VERSION 5.7 ;
  NOWIREEXTENSIONATPIN ON ;
  DIVIDERCHAR "/" ;
  BUSBITCHARS "[]" ;
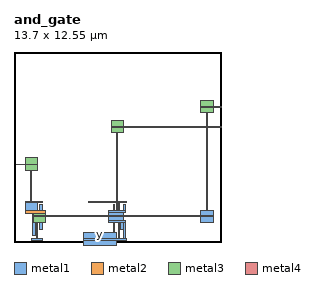
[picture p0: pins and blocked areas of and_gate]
MACRO and_gate
  CLASS BLOCK ;
  FOREIGN and_gate ;
  ORIGIN 1.150 0.200 ;
  SIZE 13.700 BY 12.550 ;
  PIN y
    PORT
      LAYER metal1 ;
        RECT -0.400 2.400 0.750 2.500 ;
        RECT 3.800 2.400 6.250 2.500 ;
        RECT -0.400 1.900 0.400 2.400 ;
        RECT 0.550 1.900 0.700 2.300 ;
        RECT 5.450 1.900 5.500 2.300 ;
        RECT 5.750 1.900 5.800 2.400 ;
        RECT 6.100 1.900 6.200 2.250 ;
        RECT -0.400 1.700 0.950 1.900 ;
        RECT 0.050 1.100 0.950 1.700 ;
        RECT 5.100 1.750 6.200 1.900 ;
        RECT 5.100 1.550 6.100 1.750 ;
        RECT 11.200 1.550 12.000 1.900 ;
        RECT 5.100 1.500 12.000 1.550 ;
        RECT 5.100 1.200 6.100 1.500 ;
        RECT 5.100 1.100 6.200 1.200 ;
        RECT 11.200 1.100 12.000 1.500 ;
        RECT 0.050 0.200 0.250 1.100 ;
        RECT 0.350 0.050 0.400 1.100 ;
        RECT 0.550 0.650 0.700 1.100 ;
        RECT 5.450 0.400 5.500 1.100 ;
        RECT 3.450 0.050 5.650 0.400 ;
        RECT 5.750 0.050 5.800 1.100 ;
        RECT 5.900 0.650 6.050 1.100 ;
        RECT 6.100 0.050 6.200 1.100 ;
        RECT 0.000 -0.100 0.750 0.050 ;
        RECT 3.450 -0.100 6.250 0.050 ;
        RECT 3.450 -0.400 5.650 -0.100 ;
      LAYER metal2 ;
        RECT 11.200 8.350 12.000 9.150 ;
        RECT 5.300 7.000 6.100 7.800 ;
        RECT -0.400 4.550 0.400 5.350 ;
        RECT -0.050 2.500 0.000 4.550 ;
        RECT -0.400 1.900 0.400 2.500 ;
        RECT 5.650 1.900 5.700 7.000 ;
        RECT 11.550 1.900 11.600 8.350 ;
        RECT -0.400 1.700 0.950 1.900 ;
        RECT 0.150 1.100 0.950 1.700 ;
        RECT 5.100 1.100 6.100 1.900 ;
        RECT 11.200 1.100 12.000 1.900 ;
        RECT 3.450 -0.400 5.650 0.400 ;
      LAYER metal3 ;
        RECT 11.200 8.750 12.000 9.150 ;
        RECT 11.200 8.700 12.550 8.750 ;
        RECT 11.200 8.350 12.000 8.700 ;
        RECT 5.300 7.400 6.100 7.800 ;
        RECT 5.300 7.350 12.550 7.400 ;
        RECT 5.300 7.000 6.100 7.350 ;
        RECT -0.400 4.950 0.400 5.350 ;
        RECT -1.000 4.900 0.400 4.950 ;
        RECT -0.400 4.550 0.400 4.900 ;
        RECT 0.150 1.550 0.950 1.900 ;
        RECT 5.100 1.550 5.900 1.900 ;
        RECT 0.150 1.500 5.900 1.550 ;
        RECT 0.150 1.100 0.950 1.500 ;
        RECT 5.100 1.100 5.900 1.500 ;
        RECT 3.450 -0.400 5.600 0.400 ;
      LAYER metal4 ;
        RECT 3.450 -0.400 5.600 0.400 ;
    END
  END y
END and_gate
END LIBRARY

